VERSION 5.7 ;
  NOWIREEXTENSIONATPIN ON ;
  DIVIDERCHAR "/" ;
  BUSBITCHARS "[]" ;
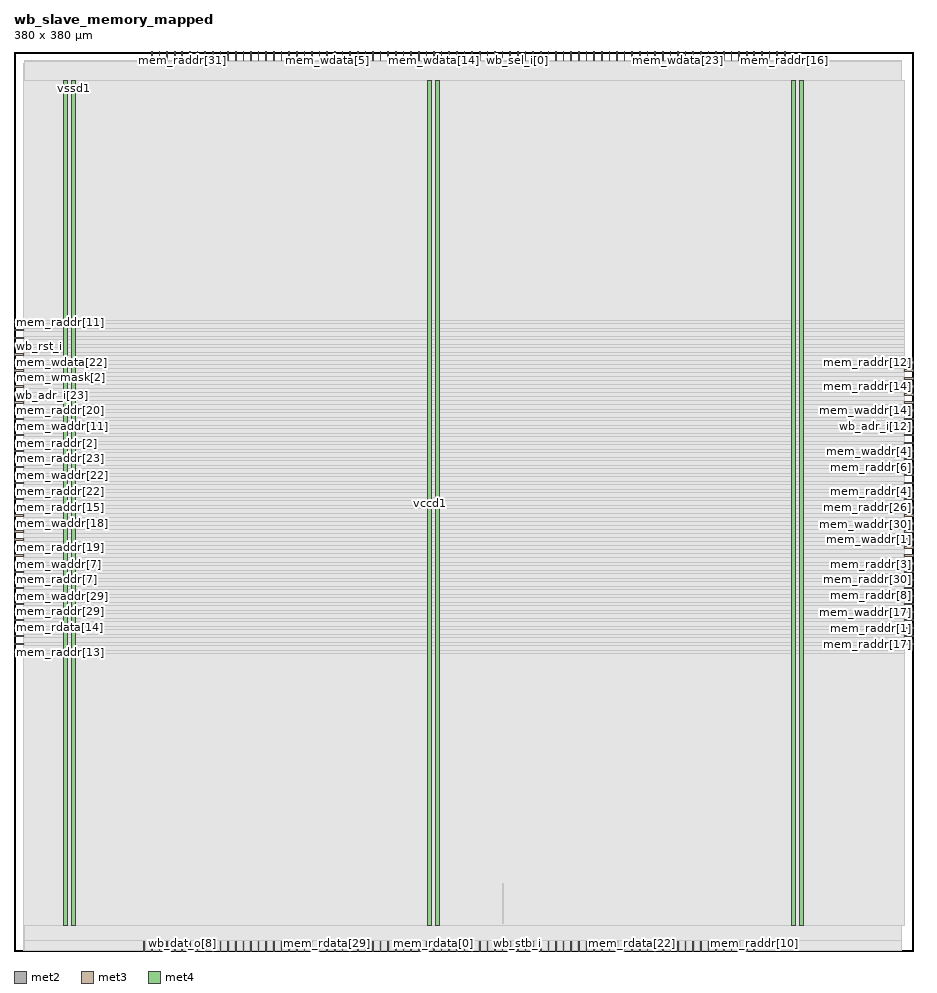
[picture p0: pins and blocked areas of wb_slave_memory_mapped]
MACRO wb_slave_memory_mapped
  CLASS BLOCK ;
  FOREIGN wb_slave_memory_mapped ;
  ORIGIN 0.000 0.000 ;
  SIZE 380.000 BY 380.000 ;
  PIN mem_raddr[0]
    DIRECTION OUTPUT ;
    USE SIGNAL ;
    ANTENNADIFFAREA 0.340600 ;
    PORT
      LAYER met2 ;
        RECT 54.830 0.000 55.110 4.000 ;
    END
  END mem_raddr[0]
  PIN mem_raddr[10]
    DIRECTION OUTPUT ;
    USE SIGNAL ;
    ANTENNADIFFAREA 0.340600 ;
    PORT
      LAYER met2 ;
        RECT 312.430 0.000 312.710 4.000 ;
    END
  END mem_raddr[10]
  PIN mem_raddr[11]
    DIRECTION OUTPUT ;
    USE SIGNAL ;
    ANTENNADIFFAREA 0.340600 ;
    PORT
      LAYER met3 ;
        RECT 0.000 265.240 4.000 265.840 ;
    END
  END mem_raddr[11]
  PIN mem_raddr[12]
    DIRECTION OUTPUT ;
    USE SIGNAL ;
    ANTENNADIFFAREA 0.340600 ;
    PORT
      LAYER met3 ;
        RECT 376.000 248.240 380.000 248.840 ;
    END
  END mem_raddr[12]
  PIN mem_raddr[13]
    DIRECTION OUTPUT ;
    USE SIGNAL ;
    ANTENNADIFFAREA 0.340600 ;
    PORT
      LAYER met3 ;
        RECT 0.000 125.840 4.000 126.440 ;
    END
  END mem_raddr[13]
  PIN mem_raddr[14]
    DIRECTION OUTPUT ;
    USE SIGNAL ;
    ANTENNADIFFAREA 0.340600 ;
    PORT
      LAYER met3 ;
        RECT 376.000 238.040 380.000 238.640 ;
    END
  END mem_raddr[14]
  PIN mem_raddr[15]
    DIRECTION OUTPUT ;
    USE SIGNAL ;
    ANTENNADIFFAREA 0.340600 ;
    PORT
      LAYER met3 ;
        RECT 0.000 187.040 4.000 187.640 ;
    END
  END mem_raddr[15]
  PIN mem_raddr[16]
    DIRECTION OUTPUT ;
    USE SIGNAL ;
    ANTENNADIFFAREA 0.340600 ;
    PORT
      LAYER met2 ;
        RECT 325.310 376.000 325.590 380.000 ;
    END
  END mem_raddr[16]
  PIN mem_raddr[17]
    DIRECTION OUTPUT ;
    USE SIGNAL ;
    ANTENNADIFFAREA 0.340600 ;
    PORT
      LAYER met3 ;
        RECT 376.000 129.240 380.000 129.840 ;
    END
  END mem_raddr[17]
  PIN mem_raddr[18]
    DIRECTION OUTPUT ;
    USE SIGNAL ;
    ANTENNADIFFAREA 0.340600 ;
    PORT
      LAYER met3 ;
        RECT 0.000 132.640 4.000 133.240 ;
    END
  END mem_raddr[18]
  PIN mem_raddr[19]
    DIRECTION OUTPUT ;
    USE SIGNAL ;
    ANTENNADIFFAREA 0.340600 ;
    PORT
      LAYER met3 ;
        RECT 0.000 170.040 4.000 170.640 ;
    END
  END mem_raddr[19]
  PIN mem_raddr[1]
    DIRECTION OUTPUT ;
    USE SIGNAL ;
    ANTENNADIFFAREA 0.340600 ;
    PORT
      LAYER met3 ;
        RECT 376.000 136.040 380.000 136.640 ;
    END
  END mem_raddr[1]
  PIN mem_raddr[20]
    DIRECTION OUTPUT ;
    USE SIGNAL ;
    ANTENNADIFFAREA 0.340600 ;
    PORT
      LAYER met3 ;
        RECT 0.000 227.840 4.000 228.440 ;
    END
  END mem_raddr[20]
  PIN mem_raddr[21]
    DIRECTION OUTPUT ;
    USE SIGNAL ;
    ANTENNADIFFAREA 0.340600 ;
    PORT
      LAYER met2 ;
        RECT 299.550 376.000 299.830 380.000 ;
    END
  END mem_raddr[21]
  PIN mem_raddr[22]
    DIRECTION OUTPUT ;
    USE SIGNAL ;
    ANTENNADIFFAREA 0.340600 ;
    PORT
      LAYER met3 ;
        RECT 0.000 193.840 4.000 194.440 ;
    END
  END mem_raddr[22]
  PIN mem_raddr[23]
    DIRECTION OUTPUT ;
    USE SIGNAL ;
    ANTENNADIFFAREA 0.340600 ;
    PORT
      LAYER met3 ;
        RECT 0.000 207.440 4.000 208.040 ;
    END
  END mem_raddr[23]
  PIN mem_raddr[24]
    DIRECTION OUTPUT ;
    USE SIGNAL ;
    ANTENNADIFFAREA 0.340600 ;
    PORT
      LAYER met3 ;
        RECT 376.000 200.640 380.000 201.240 ;
    END
  END mem_raddr[24]
  PIN mem_raddr[25]
    DIRECTION OUTPUT ;
    USE SIGNAL ;
    ANTENNADIFFAREA 0.340600 ;
    PORT
      LAYER met2 ;
        RECT 58.050 376.000 58.330 380.000 ;
    END
  END mem_raddr[25]
  PIN mem_raddr[26]
    DIRECTION OUTPUT ;
    USE SIGNAL ;
    ANTENNADIFFAREA 0.340600 ;
    PORT
      LAYER met3 ;
        RECT 376.000 187.040 380.000 187.640 ;
    END
  END mem_raddr[26]
  PIN mem_raddr[27]
    DIRECTION OUTPUT ;
    USE SIGNAL ;
    ANTENNADIFFAREA 0.340600 ;
    PORT
      LAYER met2 ;
        RECT 193.290 376.000 193.570 380.000 ;
    END
  END mem_raddr[27]
  PIN mem_raddr[28]
    DIRECTION OUTPUT ;
    USE SIGNAL ;
    ANTENNADIFFAREA 0.340600 ;
    PORT
      LAYER met2 ;
        RECT 309.210 0.000 309.490 4.000 ;
    END
  END mem_raddr[28]
  PIN mem_raddr[29]
    DIRECTION OUTPUT ;
    USE SIGNAL ;
    ANTENNADIFFAREA 0.340600 ;
    PORT
      LAYER met3 ;
        RECT 0.000 142.840 4.000 143.440 ;
    END
  END mem_raddr[29]
  PIN mem_raddr[2]
    DIRECTION OUTPUT ;
    USE SIGNAL ;
    ANTENNADIFFAREA 0.340600 ;
    PORT
      LAYER met3 ;
        RECT 0.000 210.840 4.000 211.440 ;
    END
  END mem_raddr[2]
  PIN mem_raddr[30]
    DIRECTION OUTPUT ;
    USE SIGNAL ;
    ANTENNADIFFAREA 0.340600 ;
    PORT
      LAYER met3 ;
        RECT 376.000 156.440 380.000 157.040 ;
    END
  END mem_raddr[30]
  PIN mem_raddr[31]
    DIRECTION OUTPUT ;
    USE SIGNAL ;
    ANTENNADIFFAREA 0.340600 ;
    PORT
      LAYER met2 ;
        RECT 70.930 376.000 71.210 380.000 ;
    END
  END mem_raddr[31]
  PIN mem_raddr[3]
    DIRECTION OUTPUT ;
    USE SIGNAL ;
    ANTENNADIFFAREA 0.340600 ;
    PORT
      LAYER met3 ;
        RECT 376.000 159.840 380.000 160.440 ;
    END
  END mem_raddr[3]
  PIN mem_raddr[4]
    DIRECTION OUTPUT ;
    USE SIGNAL ;
    ANTENNADIFFAREA 0.340600 ;
    PORT
      LAYER met3 ;
        RECT 376.000 190.440 380.000 191.040 ;
    END
  END mem_raddr[4]
  PIN mem_raddr[5]
    DIRECTION OUTPUT ;
    USE SIGNAL ;
    ANTENNADIFFAREA 0.340600 ;
    PORT
      LAYER met2 ;
        RECT 80.590 0.000 80.870 4.000 ;
    END
  END mem_raddr[5]
  PIN mem_raddr[6]
    DIRECTION OUTPUT ;
    USE SIGNAL ;
    ANTENNADIFFAREA 0.340600 ;
    PORT
      LAYER met3 ;
        RECT 376.000 204.040 380.000 204.640 ;
    END
  END mem_raddr[6]
  PIN mem_raddr[7]
    DIRECTION OUTPUT ;
    USE SIGNAL ;
    ANTENNADIFFAREA 0.340600 ;
    PORT
      LAYER met3 ;
        RECT 0.000 156.440 4.000 157.040 ;
    END
  END mem_raddr[7]
  PIN mem_raddr[8]
    DIRECTION OUTPUT ;
    USE SIGNAL ;
    ANTENNADIFFAREA 0.340600 ;
    PORT
      LAYER met3 ;
        RECT 376.000 153.040 380.000 153.640 ;
    END
  END mem_raddr[8]
  PIN mem_raddr[9]
    DIRECTION OUTPUT ;
    USE SIGNAL ;
    ANTENNADIFFAREA 0.340600 ;
    PORT
      LAYER met3 ;
        RECT 376.000 234.640 380.000 235.240 ;
    END
  END mem_raddr[9]
  PIN mem_rdata[0]
    DIRECTION INPUT ;
    USE SIGNAL ;
    ANTENNAGATEAREA 0.631200 ;
    ANTENNADIFFAREA 0.434700 ;
    PORT
      LAYER met2 ;
        RECT 177.190 0.000 177.470 4.000 ;
    END
  END mem_rdata[0]
  PIN mem_rdata[10]
    DIRECTION INPUT ;
    USE SIGNAL ;
    ANTENNAGATEAREA 0.631200 ;
    ANTENNADIFFAREA 0.434700 ;
    PORT
      LAYER met2 ;
        RECT 93.470 0.000 93.750 4.000 ;
    END
  END mem_rdata[10]
  PIN mem_rdata[11]
    DIRECTION INPUT ;
    USE SIGNAL ;
    ANTENNAGATEAREA 0.631200 ;
    ANTENNADIFFAREA 0.434700 ;
    PORT
      LAYER met2 ;
        RECT 190.070 0.000 190.350 4.000 ;
    END
  END mem_rdata[11]
  PIN mem_rdata[12]
    DIRECTION INPUT ;
    USE SIGNAL ;
    ANTENNAGATEAREA 0.631200 ;
    ANTENNADIFFAREA 0.434700 ;
    PORT
      LAYER met2 ;
        RECT 296.330 0.000 296.610 4.000 ;
    END
  END mem_rdata[12]
  PIN mem_rdata[13]
    DIRECTION INPUT ;
    USE SIGNAL ;
    ANTENNAGATEAREA 0.631200 ;
    ANTENNADIFFAREA 0.434700 ;
    PORT
      LAYER met2 ;
        RECT 96.690 0.000 96.970 4.000 ;
    END
  END mem_rdata[13]
  PIN mem_rdata[14]
    DIRECTION INPUT ;
    USE SIGNAL ;
    ANTENNAGATEAREA 0.631200 ;
    ANTENNADIFFAREA 0.434700 ;
    PORT
      LAYER met3 ;
        RECT 0.000 139.440 4.000 140.040 ;
    END
  END mem_rdata[14]
  PIN mem_rdata[15]
    DIRECTION INPUT ;
    USE SIGNAL ;
    ANTENNAGATEAREA 0.560700 ;
    ANTENNADIFFAREA 0.434700 ;
    PORT
      LAYER met3 ;
        RECT 0.000 129.240 4.000 129.840 ;
    END
  END mem_rdata[15]
  PIN mem_rdata[16]
    DIRECTION INPUT ;
    USE SIGNAL ;
    ANTENNAGATEAREA 0.631200 ;
    ANTENNADIFFAREA 0.434700 ;
    PORT
      LAYER met2 ;
        RECT 148.210 0.000 148.490 4.000 ;
    END
  END mem_rdata[16]
  PIN mem_rdata[17]
    DIRECTION INPUT ;
    USE SIGNAL ;
    ANTENNAGATEAREA 0.631200 ;
    ANTENNADIFFAREA 0.434700 ;
    PORT
      LAYER met2 ;
        RECT 196.510 0.000 196.790 4.000 ;
    END
  END mem_rdata[17]
  PIN mem_rdata[18]
    DIRECTION INPUT ;
    USE SIGNAL ;
    ANTENNAGATEAREA 0.631200 ;
    ANTENNADIFFAREA 0.434700 ;
    PORT
      LAYER met2 ;
        RECT 293.110 0.000 293.390 4.000 ;
    END
  END mem_rdata[18]
  PIN mem_rdata[19]
    DIRECTION INPUT ;
    USE SIGNAL ;
    ANTENNAGATEAREA 0.631200 ;
    ANTENNADIFFAREA 0.434700 ;
    PORT
      LAYER met2 ;
        RECT 231.930 0.000 232.210 4.000 ;
    END
  END mem_rdata[19]
  PIN mem_rdata[1]
    DIRECTION INPUT ;
    USE SIGNAL ;
    ANTENNAGATEAREA 0.631200 ;
    ANTENNADIFFAREA 0.434700 ;
    PORT
      LAYER met2 ;
        RECT 138.550 0.000 138.830 4.000 ;
    END
  END mem_rdata[1]
  PIN mem_rdata[20]
    DIRECTION INPUT ;
    USE SIGNAL ;
    ANTENNAGATEAREA 0.631200 ;
    ANTENNADIFFAREA 0.434700 ;
    PORT
      LAYER met2 ;
        RECT 103.130 0.000 103.410 4.000 ;
    END
  END mem_rdata[20]
  PIN mem_rdata[21]
    DIRECTION INPUT ;
    USE SIGNAL ;
    ANTENNAGATEAREA 0.631200 ;
    ANTENNADIFFAREA 0.434700 ;
    PORT
      LAYER met2 ;
        RECT 228.710 0.000 228.990 4.000 ;
    END
  END mem_rdata[21]
  PIN mem_rdata[22]
    DIRECTION INPUT ;
    USE SIGNAL ;
    ANTENNAGATEAREA 0.631200 ;
    ANTENNADIFFAREA 0.434700 ;
    PORT
      LAYER met2 ;
        RECT 260.910 0.000 261.190 4.000 ;
    END
  END mem_rdata[22]
  PIN mem_rdata[23]
    DIRECTION INPUT ;
    USE SIGNAL ;
    ANTENNAGATEAREA 0.631200 ;
    ANTENNADIFFAREA 0.434700 ;
    PORT
      LAYER met2 ;
        RECT 74.150 0.000 74.430 4.000 ;
    END
  END mem_rdata[23]
  PIN mem_rdata[24]
    DIRECTION INPUT ;
    USE SIGNAL ;
    ANTENNAGATEAREA 0.631200 ;
    ANTENNADIFFAREA 0.434700 ;
    PORT
      LAYER met2 ;
        RECT 254.470 0.000 254.750 4.000 ;
    END
  END mem_rdata[24]
  PIN mem_rdata[25]
    DIRECTION INPUT ;
    USE SIGNAL ;
    ANTENNAGATEAREA 0.631200 ;
    ANTENNADIFFAREA 0.434700 ;
    PORT
      LAYER met2 ;
        RECT 215.830 0.000 216.110 4.000 ;
    END
  END mem_rdata[25]
  PIN mem_rdata[26]
    DIRECTION INPUT ;
    USE SIGNAL ;
    ANTENNAGATEAREA 0.631200 ;
    ANTENNADIFFAREA 0.434700 ;
    PORT
      LAYER met2 ;
        RECT 167.530 0.000 167.810 4.000 ;
    END
  END mem_rdata[26]
  PIN mem_rdata[27]
    DIRECTION INPUT ;
    USE SIGNAL ;
    ANTENNAGATEAREA 0.631200 ;
    ANTENNADIFFAREA 0.434700 ;
    PORT
      LAYER met2 ;
        RECT 251.250 0.000 251.530 4.000 ;
    END
  END mem_rdata[27]
  PIN mem_rdata[28]
    DIRECTION INPUT ;
    USE SIGNAL ;
    ANTENNAGATEAREA 0.631200 ;
    ANTENNADIFFAREA 0.434700 ;
    PORT
      LAYER met2 ;
        RECT 267.350 0.000 267.630 4.000 ;
    END
  END mem_rdata[28]
  PIN mem_rdata[29]
    DIRECTION INPUT ;
    USE SIGNAL ;
    ANTENNAGATEAREA 0.631200 ;
    ANTENNADIFFAREA 0.434700 ;
    PORT
      LAYER met2 ;
        RECT 132.110 0.000 132.390 4.000 ;
    END
  END mem_rdata[29]
  PIN mem_rdata[2]
    DIRECTION INPUT ;
    USE SIGNAL ;
    ANTENNAGATEAREA 0.631200 ;
    ANTENNADIFFAREA 0.434700 ;
    PORT
      LAYER met2 ;
        RECT 106.350 0.000 106.630 4.000 ;
    END
  END mem_rdata[2]
  PIN mem_rdata[30]
    DIRECTION INPUT ;
    USE SIGNAL ;
    ANTENNAGATEAREA 0.631200 ;
    ANTENNADIFFAREA 0.434700 ;
    PORT
      LAYER met2 ;
        RECT 286.670 0.000 286.950 4.000 ;
    END
  END mem_rdata[30]
  PIN mem_rdata[31]
    DIRECTION INPUT ;
    USE SIGNAL ;
    ANTENNAGATEAREA 0.631200 ;
    ANTENNADIFFAREA 0.434700 ;
    PORT
      LAYER met2 ;
        RECT 83.810 0.000 84.090 4.000 ;
    END
  END mem_rdata[31]
  PIN mem_rdata[3]
    DIRECTION INPUT ;
    USE SIGNAL ;
    ANTENNAGATEAREA 0.631200 ;
    ANTENNADIFFAREA 0.434700 ;
    PORT
      LAYER met2 ;
        RECT 289.890 0.000 290.170 4.000 ;
    END
  END mem_rdata[3]
  PIN mem_rdata[4]
    DIRECTION INPUT ;
    USE SIGNAL ;
    ANTENNAGATEAREA 0.631200 ;
    ANTENNADIFFAREA 0.434700 ;
    PORT
      LAYER met2 ;
        RECT 154.650 0.000 154.930 4.000 ;
    END
  END mem_rdata[4]
  PIN mem_rdata[5]
    DIRECTION INPUT ;
    USE SIGNAL ;
    ANTENNAGATEAREA 0.631200 ;
    ANTENNADIFFAREA 0.434700 ;
    PORT
      LAYER met2 ;
        RECT 248.030 0.000 248.310 4.000 ;
    END
  END mem_rdata[5]
  PIN mem_rdata[6]
    DIRECTION INPUT ;
    USE SIGNAL ;
    ANTENNAGATEAREA 0.631200 ;
    ANTENNADIFFAREA 0.434700 ;
    PORT
      LAYER met2 ;
        RECT 225.490 0.000 225.770 4.000 ;
    END
  END mem_rdata[6]
  PIN mem_rdata[7]
    DIRECTION INPUT ;
    USE SIGNAL ;
    ANTENNAGATEAREA 0.631200 ;
    ANTENNADIFFAREA 0.434700 ;
    PORT
      LAYER met2 ;
        RECT 125.670 0.000 125.950 4.000 ;
    END
  END mem_rdata[7]
  PIN mem_rdata[8]
    DIRECTION INPUT ;
    USE SIGNAL ;
    ANTENNAGATEAREA 0.631200 ;
    ANTENNADIFFAREA 0.434700 ;
    PORT
      LAYER met2 ;
        RECT 170.750 0.000 171.030 4.000 ;
    END
  END mem_rdata[8]
  PIN mem_rdata[9]
    DIRECTION INPUT ;
    USE SIGNAL ;
    ANTENNAGATEAREA 0.631200 ;
    ANTENNADIFFAREA 0.434700 ;
    PORT
      LAYER met2 ;
        RECT 122.450 0.000 122.730 4.000 ;
    END
  END mem_rdata[9]
  PIN mem_rdy
    DIRECTION INPUT ;
    USE SIGNAL ;
    ANTENNAGATEAREA 0.593700 ;
    ANTENNADIFFAREA 0.434700 ;
    PORT
      LAYER met2 ;
        RECT 64.490 0.000 64.770 4.000 ;
    END
  END mem_rdy
  PIN mem_re
    DIRECTION OUTPUT ;
    USE SIGNAL ;
    ANTENNADIFFAREA 0.340600 ;
    PORT
      LAYER met2 ;
        RECT 270.570 0.000 270.850 4.000 ;
    END
  END mem_re
  PIN mem_waddr[0]
    DIRECTION OUTPUT ;
    USE SIGNAL ;
    ANTENNADIFFAREA 0.340600 ;
    PORT
      LAYER met2 ;
        RECT 119.230 0.000 119.510 4.000 ;
    END
  END mem_waddr[0]
  PIN mem_waddr[10]
    DIRECTION OUTPUT ;
    USE SIGNAL ;
    ANTENNADIFFAREA 0.340600 ;
    PORT
      LAYER met2 ;
        RECT 58.050 0.000 58.330 4.000 ;
    END
  END mem_waddr[10]
  PIN mem_waddr[11]
    DIRECTION OUTPUT ;
    USE SIGNAL ;
    ANTENNADIFFAREA 0.340600 ;
    PORT
      LAYER met3 ;
        RECT 0.000 221.040 4.000 221.640 ;
    END
  END mem_waddr[11]
  PIN mem_waddr[12]
    DIRECTION OUTPUT ;
    USE SIGNAL ;
    ANTENNADIFFAREA 0.340600 ;
    PORT
      LAYER met3 ;
        RECT 376.000 217.640 380.000 218.240 ;
    END
  END mem_waddr[12]
  PIN mem_waddr[13]
    DIRECTION OUTPUT ;
    USE SIGNAL ;
    ANTENNADIFFAREA 0.340600 ;
    PORT
      LAYER met3 ;
        RECT 0.000 251.640 4.000 252.240 ;
    END
  END mem_waddr[13]
  PIN mem_waddr[14]
    DIRECTION OUTPUT ;
    USE SIGNAL ;
    ANTENNADIFFAREA 0.340600 ;
    PORT
      LAYER met3 ;
        RECT 376.000 227.840 380.000 228.440 ;
    END
  END mem_waddr[14]
  PIN mem_waddr[15]
    DIRECTION OUTPUT ;
    USE SIGNAL ;
    ANTENNADIFFAREA 0.340600 ;
    PORT
      LAYER met3 ;
        RECT 0.000 190.440 4.000 191.040 ;
    END
  END mem_waddr[15]
  PIN mem_waddr[16]
    DIRECTION OUTPUT ;
    USE SIGNAL ;
    ANTENNADIFFAREA 0.340600 ;
    PORT
      LAYER met2 ;
        RECT 215.830 376.000 216.110 380.000 ;
    END
  END mem_waddr[16]
  PIN mem_waddr[17]
    DIRECTION OUTPUT ;
    USE SIGNAL ;
    ANTENNADIFFAREA 0.340600 ;
    PORT
      LAYER met3 ;
        RECT 376.000 139.440 380.000 140.040 ;
    END
  END mem_waddr[17]
  PIN mem_waddr[18]
    DIRECTION OUTPUT ;
    USE SIGNAL ;
    ANTENNADIFFAREA 0.340600 ;
    PORT
      LAYER met3 ;
        RECT 0.000 180.240 4.000 180.840 ;
    END
  END mem_waddr[18]
  PIN mem_waddr[19]
    DIRECTION OUTPUT ;
    USE SIGNAL ;
    ANTENNADIFFAREA 0.340600 ;
    PORT
      LAYER met3 ;
        RECT 0.000 173.440 4.000 174.040 ;
    END
  END mem_waddr[19]
  PIN mem_waddr[1]
    DIRECTION OUTPUT ;
    USE SIGNAL ;
    ANTENNADIFFAREA 0.340600 ;
    PORT
      LAYER met3 ;
        RECT 376.000 173.440 380.000 174.040 ;
    END
  END mem_waddr[1]
  PIN mem_waddr[20]
    DIRECTION OUTPUT ;
    USE SIGNAL ;
    ANTENNADIFFAREA 0.340600 ;
    PORT
      LAYER met2 ;
        RECT 83.810 376.000 84.090 380.000 ;
    END
  END mem_waddr[20]
  PIN mem_waddr[21]
    DIRECTION OUTPUT ;
    USE SIGNAL ;
    ANTENNADIFFAREA 0.340600 ;
    PORT
      LAYER met2 ;
        RECT 302.770 376.000 303.050 380.000 ;
    END
  END mem_waddr[21]
  PIN mem_waddr[22]
    DIRECTION OUTPUT ;
    USE SIGNAL ;
    ANTENNADIFFAREA 0.340600 ;
    PORT
      LAYER met3 ;
        RECT 0.000 197.240 4.000 197.840 ;
    END
  END mem_waddr[22]
  PIN mem_waddr[23]
    DIRECTION OUTPUT ;
    USE SIGNAL ;
    ANTENNADIFFAREA 0.340600 ;
    PORT
      LAYER met3 ;
        RECT 0.000 234.640 4.000 235.240 ;
    END
  END mem_waddr[23]
  PIN mem_waddr[24]
    DIRECTION OUTPUT ;
    USE SIGNAL ;
    ANTENNADIFFAREA 0.340600 ;
    PORT
      LAYER met3 ;
        RECT 376.000 197.240 380.000 197.840 ;
    END
  END mem_waddr[24]
  PIN mem_waddr[25]
    DIRECTION OUTPUT ;
    USE SIGNAL ;
    ANTENNADIFFAREA 0.340600 ;
    PORT
      LAYER met2 ;
        RECT 164.310 376.000 164.590 380.000 ;
    END
  END mem_waddr[25]
  PIN mem_waddr[26]
    DIRECTION OUTPUT ;
    USE SIGNAL ;
    ANTENNADIFFAREA 0.340600 ;
    PORT
      LAYER met3 ;
        RECT 376.000 183.640 380.000 184.240 ;
    END
  END mem_waddr[26]
  PIN mem_waddr[27]
    DIRECTION OUTPUT ;
    USE SIGNAL ;
    ANTENNADIFFAREA 0.340600 ;
    PORT
      LAYER met2 ;
        RECT 196.510 376.000 196.790 380.000 ;
    END
  END mem_waddr[27]
  PIN mem_waddr[28]
    DIRECTION OUTPUT ;
    USE SIGNAL ;
    ANTENNADIFFAREA 0.340600 ;
    PORT
      LAYER met2 ;
        RECT 302.770 0.000 303.050 4.000 ;
    END
  END mem_waddr[28]
  PIN mem_waddr[29]
    DIRECTION OUTPUT ;
    USE SIGNAL ;
    ANTENNADIFFAREA 0.340600 ;
    PORT
      LAYER met3 ;
        RECT 0.000 146.240 4.000 146.840 ;
    END
  END mem_waddr[29]
  PIN mem_waddr[2]
    DIRECTION OUTPUT ;
    USE SIGNAL ;
    ANTENNADIFFAREA 0.340600 ;
    PORT
      LAYER met3 ;
        RECT 0.000 217.640 4.000 218.240 ;
    END
  END mem_waddr[2]
  PIN mem_waddr[30]
    DIRECTION OUTPUT ;
    USE SIGNAL ;
    ANTENNADIFFAREA 0.340600 ;
    PORT
      LAYER met3 ;
        RECT 376.000 176.840 380.000 177.440 ;
    END
  END mem_waddr[30]
  PIN mem_waddr[31]
    DIRECTION OUTPUT ;
    USE SIGNAL ;
    ANTENNADIFFAREA 0.340600 ;
    PORT
      LAYER met2 ;
        RECT 148.210 376.000 148.490 380.000 ;
    END
  END mem_waddr[31]
  PIN mem_waddr[3]
    DIRECTION OUTPUT ;
    USE SIGNAL ;
    ANTENNADIFFAREA 0.340600 ;
    PORT
      LAYER met3 ;
        RECT 376.000 163.240 380.000 163.840 ;
    END
  END mem_waddr[3]
  PIN mem_waddr[4]
    DIRECTION OUTPUT ;
    USE SIGNAL ;
    ANTENNADIFFAREA 0.340600 ;
    PORT
      LAYER met3 ;
        RECT 376.000 207.440 380.000 208.040 ;
    END
  END mem_waddr[4]
  PIN mem_waddr[5]
    DIRECTION OUTPUT ;
    USE SIGNAL ;
    ANTENNADIFFAREA 0.340600 ;
    PORT
      LAYER met2 ;
        RECT 161.090 0.000 161.370 4.000 ;
    END
  END mem_waddr[5]
  PIN mem_waddr[6]
    DIRECTION OUTPUT ;
    USE SIGNAL ;
    ANTENNADIFFAREA 0.340600 ;
    PORT
      LAYER met3 ;
        RECT 376.000 210.840 380.000 211.440 ;
    END
  END mem_waddr[6]
  PIN mem_waddr[7]
    DIRECTION OUTPUT ;
    USE SIGNAL ;
    ANTENNADIFFAREA 0.340600 ;
    PORT
      LAYER met3 ;
        RECT 0.000 159.840 4.000 160.440 ;
    END
  END mem_waddr[7]
  PIN mem_waddr[8]
    DIRECTION OUTPUT ;
    USE SIGNAL ;
    ANTENNADIFFAREA 0.340600 ;
    PORT
      LAYER met3 ;
        RECT 376.000 146.240 380.000 146.840 ;
    END
  END mem_waddr[8]
  PIN mem_waddr[9]
    DIRECTION OUTPUT ;
    USE SIGNAL ;
    ANTENNADIFFAREA 0.340600 ;
    PORT
      LAYER met3 ;
        RECT 376.000 241.440 380.000 242.040 ;
    END
  END mem_waddr[9]
  PIN mem_wdata[0]
    DIRECTION OUTPUT ;
    USE SIGNAL ;
    ANTENNADIFFAREA 0.340600 ;
    PORT
      LAYER met2 ;
        RECT 90.250 376.000 90.530 380.000 ;
    END
  END mem_wdata[0]
  PIN mem_wdata[10]
    DIRECTION OUTPUT ;
    USE SIGNAL ;
    ANTENNADIFFAREA 0.340600 ;
    PORT
      LAYER met2 ;
        RECT 74.150 376.000 74.430 380.000 ;
    END
  END mem_wdata[10]
  PIN mem_wdata[11]
    DIRECTION OUTPUT ;
    USE SIGNAL ;
    ANTENNADIFFAREA 0.340600 ;
    PORT
      LAYER met2 ;
        RECT 151.430 376.000 151.710 380.000 ;
    END
  END mem_wdata[11]
  PIN mem_wdata[12]
    DIRECTION OUTPUT ;
    USE SIGNAL ;
    ANTENNADIFFAREA 0.340600 ;
    PORT
      LAYER met2 ;
        RECT 87.030 376.000 87.310 380.000 ;
    END
  END mem_wdata[12]
  PIN mem_wdata[13]
    DIRECTION OUTPUT ;
    USE SIGNAL ;
    ANTENNADIFFAREA 0.340600 ;
    PORT
      LAYER met2 ;
        RECT 96.690 376.000 96.970 380.000 ;
    END
  END mem_wdata[13]
  PIN mem_wdata[14]
    DIRECTION OUTPUT ;
    USE SIGNAL ;
    ANTENNADIFFAREA 0.340600 ;
    PORT
      LAYER met2 ;
        RECT 177.190 376.000 177.470 380.000 ;
    END
  END mem_wdata[14]
  PIN mem_wdata[15]
    DIRECTION OUTPUT ;
    USE SIGNAL ;
    ANTENNADIFFAREA 0.340600 ;
    PORT
      LAYER met2 ;
        RECT 309.210 376.000 309.490 380.000 ;
    END
  END mem_wdata[15]
  PIN mem_wdata[16]
    DIRECTION OUTPUT ;
    USE SIGNAL ;
    ANTENNADIFFAREA 0.340600 ;
    PORT
      LAYER met2 ;
        RECT 289.890 376.000 290.170 380.000 ;
    END
  END mem_wdata[16]
  PIN mem_wdata[17]
    DIRECTION OUTPUT ;
    USE SIGNAL ;
    ANTENNADIFFAREA 0.340600 ;
    PORT
      LAYER met2 ;
        RECT 283.450 376.000 283.730 380.000 ;
    END
  END mem_wdata[17]
  PIN mem_wdata[18]
    DIRECTION OUTPUT ;
    USE SIGNAL ;
    ANTENNADIFFAREA 0.340600 ;
    PORT
      LAYER met2 ;
        RECT 186.850 376.000 187.130 380.000 ;
    END
  END mem_wdata[18]
  PIN mem_wdata[19]
    DIRECTION OUTPUT ;
    USE SIGNAL ;
    ANTENNADIFFAREA 0.340600 ;
    PORT
      LAYER met2 ;
        RECT 254.470 376.000 254.750 380.000 ;
    END
  END mem_wdata[19]
  PIN mem_wdata[1]
    DIRECTION OUTPUT ;
    USE SIGNAL ;
    ANTENNADIFFAREA 0.340600 ;
    PORT
      LAYER met2 ;
        RECT 93.470 376.000 93.750 380.000 ;
    END
  END mem_wdata[1]
  PIN mem_wdata[20]
    DIRECTION OUTPUT ;
    USE SIGNAL ;
    ANTENNADIFFAREA 0.340600 ;
    PORT
      LAYER met2 ;
        RECT 128.890 376.000 129.170 380.000 ;
    END
  END mem_wdata[20]
  PIN mem_wdata[21]
    DIRECTION OUTPUT ;
    USE SIGNAL ;
    ANTENNADIFFAREA 0.340600 ;
    PORT
      LAYER met2 ;
        RECT 80.590 376.000 80.870 380.000 ;
    END
  END mem_wdata[21]
  PIN mem_wdata[22]
    DIRECTION OUTPUT ;
    USE SIGNAL ;
    ANTENNADIFFAREA 0.340600 ;
    PORT
      LAYER met3 ;
        RECT 0.000 248.240 4.000 248.840 ;
    END
  END mem_wdata[22]
  PIN mem_wdata[23]
    DIRECTION OUTPUT ;
    USE SIGNAL ;
    ANTENNADIFFAREA 0.340600 ;
    PORT
      LAYER met2 ;
        RECT 280.230 376.000 280.510 380.000 ;
    END
  END mem_wdata[23]
  PIN mem_wdata[24]
    DIRECTION OUTPUT ;
    USE SIGNAL ;
    ANTENNADIFFAREA 0.340600 ;
    PORT
      LAYER met2 ;
        RECT 135.330 376.000 135.610 380.000 ;
    END
  END mem_wdata[24]
  PIN mem_wdata[25]
    DIRECTION OUTPUT ;
    USE SIGNAL ;
    ANTENNADIFFAREA 0.340600 ;
    PORT
      LAYER met2 ;
        RECT 116.010 376.000 116.290 380.000 ;
    END
  END mem_wdata[25]
  PIN mem_wdata[26]
    DIRECTION OUTPUT ;
    USE SIGNAL ;
    ANTENNADIFFAREA 0.340600 ;
    PORT
      LAYER met2 ;
        RECT 248.030 376.000 248.310 380.000 ;
    END
  END mem_wdata[26]
  PIN mem_wdata[27]
    DIRECTION OUTPUT ;
    USE SIGNAL ;
    ANTENNADIFFAREA 0.340600 ;
    PORT
      LAYER met2 ;
        RECT 293.110 376.000 293.390 380.000 ;
    END
  END mem_wdata[27]
  PIN mem_wdata[28]
    DIRECTION OUTPUT ;
    USE SIGNAL ;
    ANTENNADIFFAREA 0.340600 ;
    PORT
      LAYER met2 ;
        RECT 141.770 376.000 142.050 380.000 ;
    END
  END mem_wdata[28]
  PIN mem_wdata[29]
    DIRECTION OUTPUT ;
    USE SIGNAL ;
    ANTENNADIFFAREA 0.340600 ;
    PORT
      LAYER met2 ;
        RECT 170.750 376.000 171.030 380.000 ;
    END
  END mem_wdata[29]
  PIN mem_wdata[2]
    DIRECTION OUTPUT ;
    USE SIGNAL ;
    ANTENNADIFFAREA 0.340600 ;
    PORT
      LAYER met2 ;
        RECT 251.250 376.000 251.530 380.000 ;
    END
  END mem_wdata[2]
  PIN mem_wdata[30]
    DIRECTION OUTPUT ;
    USE SIGNAL ;
    ANTENNADIFFAREA 0.340600 ;
    PORT
      LAYER met2 ;
        RECT 106.350 376.000 106.630 380.000 ;
    END
  END mem_wdata[30]
  PIN mem_wdata[31]
    DIRECTION OUTPUT ;
    USE SIGNAL ;
    ANTENNADIFFAREA 0.340600 ;
    PORT
      LAYER met2 ;
        RECT 238.370 376.000 238.650 380.000 ;
    END
  END mem_wdata[31]
  PIN mem_wdata[3]
    DIRECTION OUTPUT ;
    USE SIGNAL ;
    ANTENNADIFFAREA 0.340600 ;
    PORT
      LAYER met2 ;
        RECT 235.150 376.000 235.430 380.000 ;
    END
  END mem_wdata[3]
  PIN mem_wdata[4]
    DIRECTION OUTPUT ;
    USE SIGNAL ;
    ANTENNADIFFAREA 0.340600 ;
    PORT
      LAYER met2 ;
        RECT 228.710 376.000 228.990 380.000 ;
    END
  END mem_wdata[4]
  PIN mem_wdata[5]
    DIRECTION OUTPUT ;
    USE SIGNAL ;
    ANTENNADIFFAREA 0.340600 ;
    PORT
      LAYER met2 ;
        RECT 132.110 376.000 132.390 380.000 ;
    END
  END mem_wdata[5]
  PIN mem_wdata[6]
    DIRECTION OUTPUT ;
    USE SIGNAL ;
    ANTENNADIFFAREA 0.340600 ;
    PORT
      LAYER met2 ;
        RECT 312.430 376.000 312.710 380.000 ;
    END
  END mem_wdata[6]
  PIN mem_wdata[7]
    DIRECTION OUTPUT ;
    USE SIGNAL ;
    ANTENNADIFFAREA 0.340600 ;
    PORT
      LAYER met2 ;
        RECT 99.910 376.000 100.190 380.000 ;
    END
  END mem_wdata[7]
  PIN mem_wdata[8]
    DIRECTION OUTPUT ;
    USE SIGNAL ;
    ANTENNADIFFAREA 0.340600 ;
    PORT
      LAYER met2 ;
        RECT 241.590 376.000 241.870 380.000 ;
    END
  END mem_wdata[8]
  PIN mem_wdata[9]
    DIRECTION OUTPUT ;
    USE SIGNAL ;
    ANTENNADIFFAREA 0.340600 ;
    PORT
      LAYER met2 ;
        RECT 315.650 376.000 315.930 380.000 ;
    END
  END mem_wdata[9]
  PIN mem_we
    DIRECTION OUTPUT ;
    USE SIGNAL ;
    ANTENNADIFFAREA 0.340600 ;
    PORT
      LAYER met2 ;
        RECT 186.850 0.000 187.130 4.000 ;
    END
  END mem_we
  PIN mem_wmask[0]
    DIRECTION OUTPUT ;
    USE SIGNAL ;
    ANTENNADIFFAREA 0.340600 ;
    PORT
      LAYER met2 ;
        RECT 219.050 376.000 219.330 380.000 ;
    END
  END mem_wmask[0]
  PIN mem_wmask[1]
    DIRECTION OUTPUT ;
    USE SIGNAL ;
    ANTENNADIFFAREA 0.340600 ;
    PORT
      LAYER met2 ;
        RECT 296.330 376.000 296.610 380.000 ;
    END
  END mem_wmask[1]
  PIN mem_wmask[2]
    DIRECTION OUTPUT ;
    USE SIGNAL ;
    ANTENNADIFFAREA 0.340600 ;
    PORT
      LAYER met3 ;
        RECT 0.000 244.840 4.000 245.440 ;
    END
  END mem_wmask[2]
  PIN mem_wmask[3]
    DIRECTION OUTPUT ;
    USE SIGNAL ;
    ANTENNADIFFAREA 0.340600 ;
    PORT
      LAYER met2 ;
        RECT 257.690 376.000 257.970 380.000 ;
    END
  END mem_wmask[3]
  PIN mem_wr_data_ack
    DIRECTION INPUT ;
    USE SIGNAL ;
    ANTENNAGATEAREA 0.631200 ;
    ANTENNADIFFAREA 0.434700 ;
    PORT
      LAYER met2 ;
        RECT 173.970 0.000 174.250 4.000 ;
    END
  END mem_wr_data_ack
  PIN up_soft_reset
    DIRECTION INPUT ;
    USE SIGNAL ;
    ANTENNAGATEAREA 0.647700 ;
    ANTENNADIFFAREA 0.434700 ;
    PORT
      LAYER met3 ;
        RECT 0.000 261.840 4.000 262.440 ;
    END
  END up_soft_reset
  PIN vccd1
    DIRECTION INOUT ;
    USE POWER ;
    PORT
      LAYER met4 ;
        RECT 21.040 10.640 22.640 367.440 ;
    END
    PORT
      LAYER met4 ;
        RECT 174.640 10.640 176.240 367.440 ;
    END
    PORT
      LAYER met4 ;
        RECT 328.240 10.640 329.840 367.440 ;
    END
  END vccd1
  PIN vssd1
    DIRECTION INOUT ;
    USE GROUND ;
    PORT
      LAYER met4 ;
        RECT 24.340 10.640 25.940 367.440 ;
    END
    PORT
      LAYER met4 ;
        RECT 177.940 10.640 179.540 367.440 ;
    END
    PORT
      LAYER met4 ;
        RECT 331.540 10.640 333.140 367.440 ;
    END
  END vssd1
  PIN wb_ack_o
    DIRECTION OUTPUT ;
    USE SIGNAL ;
    ANTENNADIFFAREA 1.782000 ;
    PORT
      LAYER met2 ;
        RECT 202.950 0.000 203.230 4.000 ;
    END
  END wb_ack_o
  PIN wb_adr_i[0]
    DIRECTION INPUT ;
    USE SIGNAL ;
    ANTENNAGATEAREA 0.560700 ;
    ANTENNADIFFAREA 0.434700 ;
    PORT
      LAYER met3 ;
        RECT 0.000 153.040 4.000 153.640 ;
    END
  END wb_adr_i[0]
  PIN wb_adr_i[10]
    DIRECTION INPUT ;
    USE SIGNAL ;
    ANTENNAGATEAREA 0.560700 ;
    ANTENNADIFFAREA 0.434700 ;
    PORT
      LAYER met2 ;
        RECT 180.410 0.000 180.690 4.000 ;
    END
  END wb_adr_i[10]
  PIN wb_adr_i[11]
    DIRECTION INPUT ;
    USE SIGNAL ;
    ANTENNAGATEAREA 0.560700 ;
    ANTENNADIFFAREA 0.434700 ;
    PORT
      LAYER met3 ;
        RECT 0.000 224.440 4.000 225.040 ;
    END
  END wb_adr_i[11]
  PIN wb_adr_i[12]
    DIRECTION INPUT ;
    USE SIGNAL ;
    ANTENNAGATEAREA 0.560700 ;
    ANTENNADIFFAREA 0.434700 ;
    PORT
      LAYER met3 ;
        RECT 376.000 221.040 380.000 221.640 ;
    END
  END wb_adr_i[12]
  PIN wb_adr_i[13]
    DIRECTION INPUT ;
    USE SIGNAL ;
    ANTENNAGATEAREA 0.560700 ;
    ANTENNADIFFAREA 0.434700 ;
    PORT
      LAYER met3 ;
        RECT 0.000 204.040 4.000 204.640 ;
    END
  END wb_adr_i[13]
  PIN wb_adr_i[14]
    DIRECTION INPUT ;
    USE SIGNAL ;
    ANTENNAGATEAREA 0.560700 ;
    ANTENNADIFFAREA 0.434700 ;
    PORT
      LAYER met3 ;
        RECT 376.000 214.240 380.000 214.840 ;
    END
  END wb_adr_i[14]
  PIN wb_adr_i[15]
    DIRECTION INPUT ;
    USE SIGNAL ;
    ANTENNAGATEAREA 0.560700 ;
    ANTENNADIFFAREA 0.434700 ;
    PORT
      LAYER met3 ;
        RECT 0.000 183.640 4.000 184.240 ;
    END
  END wb_adr_i[15]
  PIN wb_adr_i[16]
    DIRECTION INPUT ;
    USE SIGNAL ;
    ANTENNAGATEAREA 0.560700 ;
    ANTENNADIFFAREA 0.434700 ;
    PORT
      LAYER met2 ;
        RECT 209.390 376.000 209.670 380.000 ;
    END
  END wb_adr_i[16]
  PIN wb_adr_i[17]
    DIRECTION INPUT ;
    USE SIGNAL ;
    ANTENNAGATEAREA 0.560700 ;
    ANTENNADIFFAREA 0.434700 ;
    PORT
      LAYER met3 ;
        RECT 376.000 142.840 380.000 143.440 ;
    END
  END wb_adr_i[17]
  PIN wb_adr_i[18]
    DIRECTION INPUT ;
    USE SIGNAL ;
    ANTENNAGATEAREA 0.560700 ;
    ANTENNADIFFAREA 0.434700 ;
    PORT
      LAYER met3 ;
        RECT 0.000 176.840 4.000 177.440 ;
    END
  END wb_adr_i[18]
  PIN wb_adr_i[19]
    DIRECTION INPUT ;
    USE SIGNAL ;
    ANTENNAGATEAREA 0.560700 ;
    ANTENNADIFFAREA 0.434700 ;
    PORT
      LAYER met3 ;
        RECT 0.000 166.640 4.000 167.240 ;
    END
  END wb_adr_i[19]
  PIN wb_adr_i[1]
    DIRECTION INPUT ;
    USE SIGNAL ;
    ANTENNAGATEAREA 0.560700 ;
    ANTENNADIFFAREA 0.434700 ;
    PORT
      LAYER met3 ;
        RECT 376.000 170.040 380.000 170.640 ;
    END
  END wb_adr_i[1]
  PIN wb_adr_i[20]
    DIRECTION INPUT ;
    USE SIGNAL ;
    ANTENNAGATEAREA 0.560700 ;
    ANTENNADIFFAREA 0.434700 ;
    PORT
      LAYER met2 ;
        RECT 77.370 376.000 77.650 380.000 ;
    END
  END wb_adr_i[20]
  PIN wb_adr_i[21]
    DIRECTION INPUT ;
    USE SIGNAL ;
    ANTENNAGATEAREA 0.560700 ;
    ANTENNADIFFAREA 0.434700 ;
    PORT
      LAYER met2 ;
        RECT 202.950 376.000 203.230 380.000 ;
    END
  END wb_adr_i[21]
  PIN wb_adr_i[22]
    DIRECTION INPUT ;
    USE SIGNAL ;
    ANTENNAGATEAREA 0.560700 ;
    ANTENNADIFFAREA 0.434700 ;
    PORT
      LAYER met3 ;
        RECT 0.000 200.640 4.000 201.240 ;
    END
  END wb_adr_i[22]
  PIN wb_adr_i[23]
    DIRECTION INPUT ;
    USE SIGNAL ;
    ANTENNAGATEAREA 0.560700 ;
    ANTENNADIFFAREA 0.434700 ;
    PORT
      LAYER met3 ;
        RECT 0.000 231.240 4.000 231.840 ;
    END
  END wb_adr_i[23]
  PIN wb_adr_i[24]
    DIRECTION INPUT ;
    USE SIGNAL ;
    ANTENNAGATEAREA 0.560700 ;
    ANTENNADIFFAREA 0.434700 ;
    PORT
      LAYER met3 ;
        RECT 376.000 193.840 380.000 194.440 ;
    END
  END wb_adr_i[24]
  PIN wb_adr_i[25]
    DIRECTION INPUT ;
    USE SIGNAL ;
    ANTENNAGATEAREA 0.560700 ;
    ANTENNADIFFAREA 0.434700 ;
    PORT
      LAYER met2 ;
        RECT 154.650 376.000 154.930 380.000 ;
    END
  END wb_adr_i[25]
  PIN wb_adr_i[26]
    DIRECTION INPUT ;
    USE SIGNAL ;
    ANTENNAGATEAREA 0.560700 ;
    ANTENNADIFFAREA 0.434700 ;
    PORT
      LAYER met3 ;
        RECT 376.000 180.240 380.000 180.840 ;
    END
  END wb_adr_i[26]
  PIN wb_adr_i[27]
    DIRECTION INPUT ;
    USE SIGNAL ;
    ANTENNAGATEAREA 0.560700 ;
    ANTENNADIFFAREA 0.434700 ;
    PORT
      LAYER met2 ;
        RECT 190.070 376.000 190.350 380.000 ;
    END
  END wb_adr_i[27]
  PIN wb_adr_i[28]
    DIRECTION INPUT ;
    USE SIGNAL ;
    ANTENNAGATEAREA 0.560700 ;
    ANTENNADIFFAREA 0.434700 ;
    PORT
      LAYER met2 ;
        RECT 209.390 0.000 209.670 4.000 ;
    END
  END wb_adr_i[28]
  PIN wb_adr_i[29]
    DIRECTION INPUT ;
    USE SIGNAL ;
    ANTENNAGATEAREA 0.560700 ;
    ANTENNADIFFAREA 0.434700 ;
    PORT
      LAYER met3 ;
        RECT 0.000 149.640 4.000 150.240 ;
    END
  END wb_adr_i[29]
  PIN wb_adr_i[2]
    DIRECTION INPUT ;
    USE SIGNAL ;
    ANTENNAGATEAREA 0.560700 ;
    ANTENNADIFFAREA 0.434700 ;
    PORT
      LAYER met3 ;
        RECT 0.000 214.240 4.000 214.840 ;
    END
  END wb_adr_i[2]
  PIN wb_adr_i[30]
    DIRECTION INPUT ;
    USE SIGNAL ;
    ANTENNAGATEAREA 0.560700 ;
    ANTENNADIFFAREA 0.434700 ;
    PORT
      LAYER met3 ;
        RECT 376.000 132.640 380.000 133.240 ;
    END
  END wb_adr_i[30]
  PIN wb_adr_i[31]
    DIRECTION INPUT ;
    USE SIGNAL ;
    ANTENNAGATEAREA 0.560700 ;
    ANTENNADIFFAREA 0.434700 ;
    PORT
      LAYER met2 ;
        RECT 167.530 376.000 167.810 380.000 ;
    END
  END wb_adr_i[31]
  PIN wb_adr_i[3]
    DIRECTION INPUT ;
    USE SIGNAL ;
    ANTENNAGATEAREA 0.560700 ;
    ANTENNADIFFAREA 0.434700 ;
    PORT
      LAYER met3 ;
        RECT 376.000 166.640 380.000 167.240 ;
    END
  END wb_adr_i[3]
  PIN wb_adr_i[4]
    DIRECTION INPUT ;
    USE SIGNAL ;
    ANTENNAGATEAREA 0.560700 ;
    ANTENNADIFFAREA 0.434700 ;
    PORT
      LAYER met3 ;
        RECT 376.000 244.840 380.000 245.440 ;
    END
  END wb_adr_i[4]
  PIN wb_adr_i[5]
    DIRECTION INPUT ;
    USE SIGNAL ;
    ANTENNAGATEAREA 0.560700 ;
    ANTENNADIFFAREA 0.434700 ;
    PORT
      LAYER met2 ;
        RECT 164.310 0.000 164.590 4.000 ;
    END
  END wb_adr_i[5]
  PIN wb_adr_i[6]
    DIRECTION INPUT ;
    USE SIGNAL ;
    ANTENNAGATEAREA 0.560700 ;
    ANTENNADIFFAREA 0.434700 ;
    PORT
      LAYER met3 ;
        RECT 376.000 224.440 380.000 225.040 ;
    END
  END wb_adr_i[6]
  PIN wb_adr_i[7]
    DIRECTION INPUT ;
    USE SIGNAL ;
    ANTENNAGATEAREA 0.560700 ;
    ANTENNADIFFAREA 0.434700 ;
    PORT
      LAYER met3 ;
        RECT 0.000 163.240 4.000 163.840 ;
    END
  END wb_adr_i[7]
  PIN wb_adr_i[8]
    DIRECTION INPUT ;
    USE SIGNAL ;
    ANTENNAGATEAREA 0.560700 ;
    ANTENNADIFFAREA 0.434700 ;
    PORT
      LAYER met3 ;
        RECT 376.000 149.640 380.000 150.240 ;
    END
  END wb_adr_i[8]
  PIN wb_adr_i[9]
    DIRECTION INPUT ;
    USE SIGNAL ;
    ANTENNAGATEAREA 0.560700 ;
    ANTENNADIFFAREA 0.434700 ;
    PORT
      LAYER met3 ;
        RECT 376.000 231.240 380.000 231.840 ;
    END
  END wb_adr_i[9]
  PIN wb_clk_i
    DIRECTION INPUT ;
    USE SIGNAL ;
    ANTENNAGATEAREA 1.286700 ;
    ANTENNADIFFAREA 0.434700 ;
    PORT
      LAYER met2 ;
        RECT 90.250 0.000 90.530 4.000 ;
    END
  END wb_clk_i
  PIN wb_cyc_i
    DIRECTION INPUT ;
    USE SIGNAL ;
    ANTENNAGATEAREA 0.560700 ;
    ANTENNADIFFAREA 0.434700 ;
    PORT
      LAYER met2 ;
        RECT 193.290 0.000 193.570 4.000 ;
    END
  END wb_cyc_i
  PIN wb_dat_i[0]
    DIRECTION INPUT ;
    USE SIGNAL ;
    ANTENNAGATEAREA 0.560700 ;
    ANTENNADIFFAREA 0.434700 ;
    PORT
      LAYER met2 ;
        RECT 67.710 376.000 67.990 380.000 ;
    END
  END wb_dat_i[0]
  PIN wb_dat_i[10]
    DIRECTION INPUT ;
    USE SIGNAL ;
    ANTENNAGATEAREA 0.560700 ;
    ANTENNADIFFAREA 0.434700 ;
    PORT
      LAYER met2 ;
        RECT 112.790 376.000 113.070 380.000 ;
    END
  END wb_dat_i[10]
  PIN wb_dat_i[11]
    DIRECTION INPUT ;
    USE SIGNAL ;
    ANTENNAGATEAREA 0.560700 ;
    ANTENNADIFFAREA 0.434700 ;
    PORT
      LAYER met2 ;
        RECT 119.230 376.000 119.510 380.000 ;
    END
  END wb_dat_i[11]
  PIN wb_dat_i[12]
    DIRECTION INPUT ;
    USE SIGNAL ;
    ANTENNAGATEAREA 0.560700 ;
    ANTENNADIFFAREA 0.434700 ;
    PORT
      LAYER met2 ;
        RECT 125.670 376.000 125.950 380.000 ;
    END
  END wb_dat_i[12]
  PIN wb_dat_i[13]
    DIRECTION INPUT ;
    USE SIGNAL ;
    ANTENNAGATEAREA 0.560700 ;
    ANTENNADIFFAREA 0.434700 ;
    PORT
      LAYER met3 ;
        RECT 0.000 258.440 4.000 259.040 ;
    END
  END wb_dat_i[13]
  PIN wb_dat_i[14]
    DIRECTION INPUT ;
    USE SIGNAL ;
    ANTENNAGATEAREA 0.560700 ;
    ANTENNADIFFAREA 0.434700 ;
    PORT
      LAYER met2 ;
        RECT 180.410 376.000 180.690 380.000 ;
    END
  END wb_dat_i[14]
  PIN wb_dat_i[15]
    DIRECTION INPUT ;
    USE SIGNAL ;
    ANTENNAGATEAREA 0.560700 ;
    ANTENNADIFFAREA 0.434700 ;
    PORT
      LAYER met2 ;
        RECT 318.870 376.000 319.150 380.000 ;
    END
  END wb_dat_i[15]
  PIN wb_dat_i[16]
    DIRECTION INPUT ;
    USE SIGNAL ;
    ANTENNAGATEAREA 0.560700 ;
    ANTENNADIFFAREA 0.434700 ;
    PORT
      LAYER met2 ;
        RECT 286.670 376.000 286.950 380.000 ;
    END
  END wb_dat_i[16]
  PIN wb_dat_i[17]
    DIRECTION INPUT ;
    USE SIGNAL ;
    ANTENNAGATEAREA 0.560700 ;
    ANTENNADIFFAREA 0.434700 ;
    PORT
      LAYER met2 ;
        RECT 260.910 376.000 261.190 380.000 ;
    END
  END wb_dat_i[17]
  PIN wb_dat_i[18]
    DIRECTION INPUT ;
    USE SIGNAL ;
    ANTENNAGATEAREA 0.560700 ;
    ANTENNADIFFAREA 0.434700 ;
    PORT
      LAYER met2 ;
        RECT 183.630 376.000 183.910 380.000 ;
    END
  END wb_dat_i[18]
  PIN wb_dat_i[19]
    DIRECTION INPUT ;
    USE SIGNAL ;
    ANTENNAGATEAREA 0.560700 ;
    ANTENNADIFFAREA 0.434700 ;
    PORT
      LAYER met2 ;
        RECT 264.130 376.000 264.410 380.000 ;
    END
  END wb_dat_i[19]
  PIN wb_dat_i[1]
    DIRECTION INPUT ;
    USE SIGNAL ;
    ANTENNAGATEAREA 0.560700 ;
    ANTENNADIFFAREA 0.434700 ;
    PORT
      LAYER met2 ;
        RECT 61.270 376.000 61.550 380.000 ;
    END
  END wb_dat_i[1]
  PIN wb_dat_i[20]
    DIRECTION INPUT ;
    USE SIGNAL ;
    ANTENNAGATEAREA 0.560700 ;
    ANTENNADIFFAREA 0.434700 ;
    PORT
      LAYER met2 ;
        RECT 109.570 376.000 109.850 380.000 ;
    END
  END wb_dat_i[20]
  PIN wb_dat_i[21]
    DIRECTION INPUT ;
    USE SIGNAL ;
    ANTENNAGATEAREA 0.560700 ;
    ANTENNADIFFAREA 0.434700 ;
    PORT
      LAYER met2 ;
        RECT 122.450 376.000 122.730 380.000 ;
    END
  END wb_dat_i[21]
  PIN wb_dat_i[22]
    DIRECTION INPUT ;
    USE SIGNAL ;
    ANTENNAGATEAREA 0.560700 ;
    ANTENNADIFFAREA 0.434700 ;
    PORT
      LAYER met3 ;
        RECT 0.000 241.440 4.000 242.040 ;
    END
  END wb_dat_i[22]
  PIN wb_dat_i[23]
    DIRECTION INPUT ;
    USE SIGNAL ;
    ANTENNAGATEAREA 0.560700 ;
    ANTENNADIFFAREA 0.434700 ;
    PORT
      LAYER met2 ;
        RECT 222.270 376.000 222.550 380.000 ;
    END
  END wb_dat_i[23]
  PIN wb_dat_i[24]
    DIRECTION INPUT ;
    USE SIGNAL ;
    ANTENNAGATEAREA 0.560700 ;
    ANTENNADIFFAREA 0.434700 ;
    PORT
      LAYER met2 ;
        RECT 103.130 376.000 103.410 380.000 ;
    END
  END wb_dat_i[24]
  PIN wb_dat_i[25]
    DIRECTION INPUT ;
    USE SIGNAL ;
    ANTENNAGATEAREA 0.560700 ;
    ANTENNADIFFAREA 0.434700 ;
    PORT
      LAYER met2 ;
        RECT 161.090 376.000 161.370 380.000 ;
    END
  END wb_dat_i[25]
  PIN wb_dat_i[26]
    DIRECTION INPUT ;
    USE SIGNAL ;
    ANTENNAGATEAREA 0.560700 ;
    ANTENNADIFFAREA 0.434700 ;
    PORT
      LAYER met2 ;
        RECT 244.810 376.000 245.090 380.000 ;
    END
  END wb_dat_i[26]
  PIN wb_dat_i[27]
    DIRECTION INPUT ;
    USE SIGNAL ;
    ANTENNAGATEAREA 0.560700 ;
    ANTENNADIFFAREA 0.434700 ;
    PORT
      LAYER met2 ;
        RECT 206.170 376.000 206.450 380.000 ;
    END
  END wb_dat_i[27]
  PIN wb_dat_i[28]
    DIRECTION INPUT ;
    USE SIGNAL ;
    ANTENNAGATEAREA 0.560700 ;
    ANTENNADIFFAREA 0.434700 ;
    PORT
      LAYER met2 ;
        RECT 64.490 376.000 64.770 380.000 ;
    END
  END wb_dat_i[28]
  PIN wb_dat_i[29]
    DIRECTION INPUT ;
    USE SIGNAL ;
    ANTENNAGATEAREA 0.560700 ;
    ANTENNADIFFAREA 0.434700 ;
    PORT
      LAYER met2 ;
        RECT 173.970 376.000 174.250 380.000 ;
    END
  END wb_dat_i[29]
  PIN wb_dat_i[2]
    DIRECTION INPUT ;
    USE SIGNAL ;
    ANTENNAGATEAREA 0.560700 ;
    ANTENNADIFFAREA 0.434700 ;
    PORT
      LAYER met2 ;
        RECT 267.350 376.000 267.630 380.000 ;
    END
  END wb_dat_i[2]
  PIN wb_dat_i[30]
    DIRECTION INPUT ;
    USE SIGNAL ;
    ANTENNAGATEAREA 0.560700 ;
    ANTENNADIFFAREA 0.434700 ;
    PORT
      LAYER met2 ;
        RECT 144.990 376.000 145.270 380.000 ;
    END
  END wb_dat_i[30]
  PIN wb_dat_i[31]
    DIRECTION INPUT ;
    USE SIGNAL ;
    ANTENNAGATEAREA 0.560700 ;
    ANTENNADIFFAREA 0.434700 ;
    PORT
      LAYER met2 ;
        RECT 273.790 376.000 274.070 380.000 ;
    END
  END wb_dat_i[31]
  PIN wb_dat_i[3]
    DIRECTION INPUT ;
    USE SIGNAL ;
    ANTENNAGATEAREA 0.560700 ;
    ANTENNADIFFAREA 0.434700 ;
    PORT
      LAYER met2 ;
        RECT 231.930 376.000 232.210 380.000 ;
    END
  END wb_dat_i[3]
  PIN wb_dat_i[4]
    DIRECTION INPUT ;
    USE SIGNAL ;
    ANTENNAGATEAREA 0.560700 ;
    ANTENNADIFFAREA 0.434700 ;
    PORT
      LAYER met2 ;
        RECT 277.010 376.000 277.290 380.000 ;
    END
  END wb_dat_i[4]
  PIN wb_dat_i[5]
    DIRECTION INPUT ;
    USE SIGNAL ;
    ANTENNAGATEAREA 0.560700 ;
    ANTENNADIFFAREA 0.434700 ;
    PORT
      LAYER met2 ;
        RECT 157.870 376.000 158.150 380.000 ;
    END
  END wb_dat_i[5]
  PIN wb_dat_i[6]
    DIRECTION INPUT ;
    USE SIGNAL ;
    ANTENNAGATEAREA 0.560700 ;
    ANTENNADIFFAREA 0.434700 ;
    PORT
      LAYER met2 ;
        RECT 199.730 376.000 200.010 380.000 ;
    END
  END wb_dat_i[6]
  PIN wb_dat_i[7]
    DIRECTION INPUT ;
    USE SIGNAL ;
    ANTENNAGATEAREA 0.560700 ;
    ANTENNADIFFAREA 0.434700 ;
    PORT
      LAYER met2 ;
        RECT 138.550 376.000 138.830 380.000 ;
    END
  END wb_dat_i[7]
  PIN wb_dat_i[8]
    DIRECTION INPUT ;
    USE SIGNAL ;
    ANTENNAGATEAREA 0.560700 ;
    ANTENNADIFFAREA 0.434700 ;
    PORT
      LAYER met2 ;
        RECT 225.490 376.000 225.770 380.000 ;
    END
  END wb_dat_i[8]
  PIN wb_dat_i[9]
    DIRECTION INPUT ;
    USE SIGNAL ;
    ANTENNAGATEAREA 0.560700 ;
    ANTENNADIFFAREA 0.434700 ;
    PORT
      LAYER met2 ;
        RECT 322.090 376.000 322.370 380.000 ;
    END
  END wb_dat_i[9]
  PIN wb_dat_o[0]
    DIRECTION OUTPUT ;
    USE SIGNAL ;
    ANTENNADIFFAREA 1.782000 ;
    PORT
      LAYER met2 ;
        RECT 183.630 0.000 183.910 4.000 ;
    END
  END wb_dat_o[0]
  PIN wb_dat_o[10]
    DIRECTION OUTPUT ;
    USE SIGNAL ;
    ANTENNADIFFAREA 1.782000 ;
    PORT
      LAYER met2 ;
        RECT 87.030 0.000 87.310 4.000 ;
    END
  END wb_dat_o[10]
  PIN wb_dat_o[11]
    DIRECTION OUTPUT ;
    USE SIGNAL ;
    ANTENNADIFFAREA 1.782000 ;
    PORT
      LAYER met2 ;
        RECT 277.010 0.000 277.290 4.000 ;
    END
  END wb_dat_o[11]
  PIN wb_dat_o[12]
    DIRECTION OUTPUT ;
    USE SIGNAL ;
    ANTENNADIFFAREA 1.782000 ;
    PORT
      LAYER met2 ;
        RECT 244.810 0.000 245.090 4.000 ;
    END
  END wb_dat_o[12]
  PIN wb_dat_o[13]
    DIRECTION OUTPUT ;
    USE SIGNAL ;
    ANTENNADIFFAREA 1.782000 ;
    PORT
      LAYER met2 ;
        RECT 144.990 0.000 145.270 4.000 ;
    END
  END wb_dat_o[13]
  PIN wb_dat_o[14]
    DIRECTION OUTPUT ;
    USE SIGNAL ;
    ANTENNADIFFAREA 1.782000 ;
    PORT
      LAYER met3 ;
        RECT 0.000 136.040 4.000 136.640 ;
    END
  END wb_dat_o[14]
  PIN wb_dat_o[15]
    DIRECTION OUTPUT ;
    USE SIGNAL ;
    ANTENNADIFFAREA 1.782000 ;
    PORT
      LAYER met2 ;
        RECT 112.790 0.000 113.070 4.000 ;
    END
  END wb_dat_o[15]
  PIN wb_dat_o[16]
    DIRECTION OUTPUT ;
    USE SIGNAL ;
    ANTENNADIFFAREA 1.782000 ;
    PORT
      LAYER met2 ;
        RECT 151.430 0.000 151.710 4.000 ;
    END
  END wb_dat_o[16]
  PIN wb_dat_o[17]
    DIRECTION OUTPUT ;
    USE SIGNAL ;
    ANTENNADIFFAREA 1.782000 ;
    PORT
      LAYER met2 ;
        RECT 238.370 0.000 238.650 4.000 ;
    END
  END wb_dat_o[17]
  PIN wb_dat_o[18]
    DIRECTION OUTPUT ;
    USE SIGNAL ;
    ANTENNADIFFAREA 1.782000 ;
    PORT
      LAYER met2 ;
        RECT 222.270 0.000 222.550 4.000 ;
    END
  END wb_dat_o[18]
  PIN wb_dat_o[19]
    DIRECTION OUTPUT ;
    USE SIGNAL ;
    ANTENNADIFFAREA 1.782000 ;
    PORT
      LAYER met2 ;
        RECT 273.790 0.000 274.070 4.000 ;
    END
  END wb_dat_o[19]
  PIN wb_dat_o[1]
    DIRECTION OUTPUT ;
    USE SIGNAL ;
    ANTENNADIFFAREA 1.782000 ;
    PORT
      LAYER met2 ;
        RECT 141.770 0.000 142.050 4.000 ;
    END
  END wb_dat_o[1]
  PIN wb_dat_o[20]
    DIRECTION OUTPUT ;
    USE SIGNAL ;
    ANTENNADIFFAREA 1.782000 ;
    PORT
      LAYER met2 ;
        RECT 99.910 0.000 100.190 4.000 ;
    END
  END wb_dat_o[20]
  PIN wb_dat_o[21]
    DIRECTION OUTPUT ;
    USE SIGNAL ;
    ANTENNADIFFAREA 1.782000 ;
    PORT
      LAYER met2 ;
        RECT 299.550 0.000 299.830 4.000 ;
    END
  END wb_dat_o[21]
  PIN wb_dat_o[22]
    DIRECTION OUTPUT ;
    USE SIGNAL ;
    ANTENNADIFFAREA 1.782000 ;
    PORT
      LAYER met2 ;
        RECT 280.230 0.000 280.510 4.000 ;
    END
  END wb_dat_o[22]
  PIN wb_dat_o[23]
    DIRECTION OUTPUT ;
    USE SIGNAL ;
    ANTENNADIFFAREA 1.782000 ;
    PORT
      LAYER met2 ;
        RECT 67.710 0.000 67.990 4.000 ;
    END
  END wb_dat_o[23]
  PIN wb_dat_o[24]
    DIRECTION OUTPUT ;
    USE SIGNAL ;
    ANTENNADIFFAREA 1.782000 ;
    PORT
      LAYER met2 ;
        RECT 264.130 0.000 264.410 4.000 ;
    END
  END wb_dat_o[24]
  PIN wb_dat_o[25]
    DIRECTION OUTPUT ;
    USE SIGNAL ;
    ANTENNADIFFAREA 1.782000 ;
    PORT
      LAYER met2 ;
        RECT 235.150 0.000 235.430 4.000 ;
    END
  END wb_dat_o[25]
  PIN wb_dat_o[26]
    DIRECTION OUTPUT ;
    USE SIGNAL ;
    ANTENNADIFFAREA 1.782000 ;
    PORT
      LAYER met2 ;
        RECT 61.270 0.000 61.550 4.000 ;
    END
  END wb_dat_o[26]
  PIN wb_dat_o[27]
    DIRECTION OUTPUT ;
    USE SIGNAL ;
    ANTENNADIFFAREA 1.782000 ;
    PORT
      LAYER met2 ;
        RECT 283.450 0.000 283.730 4.000 ;
    END
  END wb_dat_o[27]
  PIN wb_dat_o[28]
    DIRECTION OUTPUT ;
    USE SIGNAL ;
    ANTENNADIFFAREA 1.782000 ;
    PORT
      LAYER met2 ;
        RECT 305.990 0.000 306.270 4.000 ;
    END
  END wb_dat_o[28]
  PIN wb_dat_o[29]
    DIRECTION OUTPUT ;
    USE SIGNAL ;
    ANTENNADIFFAREA 1.782000 ;
    PORT
      LAYER met2 ;
        RECT 135.330 0.000 135.610 4.000 ;
    END
  END wb_dat_o[29]
  PIN wb_dat_o[2]
    DIRECTION OUTPUT ;
    USE SIGNAL ;
    ANTENNADIFFAREA 1.782000 ;
    PORT
      LAYER met2 ;
        RECT 116.010 0.000 116.290 4.000 ;
    END
  END wb_dat_o[2]
  PIN wb_dat_o[30]
    DIRECTION OUTPUT ;
    USE SIGNAL ;
    ANTENNADIFFAREA 1.782000 ;
    PORT
      LAYER met2 ;
        RECT 199.730 0.000 200.010 4.000 ;
    END
  END wb_dat_o[30]
  PIN wb_dat_o[31]
    DIRECTION OUTPUT ;
    USE SIGNAL ;
    ANTENNADIFFAREA 1.782000 ;
    PORT
      LAYER met2 ;
        RECT 77.370 0.000 77.650 4.000 ;
    END
  END wb_dat_o[31]
  PIN wb_dat_o[3]
    DIRECTION OUTPUT ;
    USE SIGNAL ;
    ANTENNADIFFAREA 1.782000 ;
    PORT
      LAYER met2 ;
        RECT 241.590 0.000 241.870 4.000 ;
    END
  END wb_dat_o[3]
  PIN wb_dat_o[4]
    DIRECTION OUTPUT ;
    USE SIGNAL ;
    ANTENNADIFFAREA 1.782000 ;
    PORT
      LAYER met2 ;
        RECT 157.870 0.000 158.150 4.000 ;
    END
  END wb_dat_o[4]
  PIN wb_dat_o[5]
    DIRECTION OUTPUT ;
    USE SIGNAL ;
    ANTENNADIFFAREA 1.782000 ;
    PORT
      LAYER met2 ;
        RECT 219.050 0.000 219.330 4.000 ;
    END
  END wb_dat_o[5]
  PIN wb_dat_o[6]
    DIRECTION OUTPUT ;
    USE SIGNAL ;
    ANTENNADIFFAREA 1.782000 ;
    PORT
      LAYER met2 ;
        RECT 257.690 0.000 257.970 4.000 ;
    END
  END wb_dat_o[6]
  PIN wb_dat_o[7]
    DIRECTION OUTPUT ;
    USE SIGNAL ;
    ANTENNADIFFAREA 1.782000 ;
    PORT
      LAYER met2 ;
        RECT 109.570 0.000 109.850 4.000 ;
    END
  END wb_dat_o[7]
  PIN wb_dat_o[8]
    DIRECTION OUTPUT ;
    USE SIGNAL ;
    ANTENNADIFFAREA 1.782000 ;
    PORT
      LAYER met2 ;
        RECT 70.930 0.000 71.210 4.000 ;
    END
  END wb_dat_o[8]
  PIN wb_dat_o[9]
    DIRECTION OUTPUT ;
    USE SIGNAL ;
    ANTENNADIFFAREA 1.782000 ;
    PORT
      LAYER met2 ;
        RECT 128.890 0.000 129.170 4.000 ;
    END
  END wb_dat_o[9]
  PIN wb_rst_i
    DIRECTION INPUT ;
    USE SIGNAL ;
    ANTENNAGATEAREA 0.647700 ;
    ANTENNADIFFAREA 0.434700 ;
    PORT
      LAYER met3 ;
        RECT 0.000 255.040 4.000 255.640 ;
    END
  END wb_rst_i
  PIN wb_sel_i[0]
    DIRECTION INPUT ;
    USE SIGNAL ;
    ANTENNAGATEAREA 0.560700 ;
    ANTENNADIFFAREA 0.434700 ;
    PORT
      LAYER met2 ;
        RECT 212.610 376.000 212.890 380.000 ;
    END
  END wb_sel_i[0]
  PIN wb_sel_i[1]
    DIRECTION INPUT ;
    USE SIGNAL ;
    ANTENNAGATEAREA 0.560700 ;
    ANTENNADIFFAREA 0.434700 ;
    PORT
      LAYER met2 ;
        RECT 305.990 376.000 306.270 380.000 ;
    END
  END wb_sel_i[1]
  PIN wb_sel_i[2]
    DIRECTION INPUT ;
    USE SIGNAL ;
    ANTENNAGATEAREA 0.560700 ;
    ANTENNADIFFAREA 0.434700 ;
    PORT
      LAYER met3 ;
        RECT 0.000 238.040 4.000 238.640 ;
    END
  END wb_sel_i[2]
  PIN wb_sel_i[3]
    DIRECTION INPUT ;
    USE SIGNAL ;
    ANTENNAGATEAREA 0.560700 ;
    ANTENNADIFFAREA 0.434700 ;
    PORT
      LAYER met2 ;
        RECT 270.570 376.000 270.850 380.000 ;
    END
  END wb_sel_i[3]
  PIN wb_stb_i
    DIRECTION INPUT ;
    USE SIGNAL ;
    ANTENNAGATEAREA 0.560700 ;
    ANTENNADIFFAREA 0.434700 ;
    PORT
      LAYER met2 ;
        RECT 212.610 0.000 212.890 4.000 ;
    END
  END wb_stb_i
  PIN wb_we_i
    DIRECTION INPUT ;
    USE SIGNAL ;
    ANTENNAGATEAREA 0.560700 ;
    ANTENNADIFFAREA 0.434700 ;
    PORT
      LAYER met2 ;
        RECT 206.170 0.000 206.450 4.000 ;
    END
  END wb_we_i
  OBS
      LAYER nwell ;
        RECT 5.330 10.795 374.630 367.390 ;
      LAYER li1 ;
        RECT 5.520 10.795 374.440 367.285 ;
      LAYER met1 ;
        RECT 4.210 0.380 374.830 374.640 ;
      LAYER met2 ;
        RECT 4.230 375.720 57.770 376.000 ;
        RECT 58.610 375.720 60.990 376.000 ;
        RECT 61.830 375.720 64.210 376.000 ;
        RECT 65.050 375.720 67.430 376.000 ;
        RECT 68.270 375.720 70.650 376.000 ;
        RECT 71.490 375.720 73.870 376.000 ;
        RECT 74.710 375.720 77.090 376.000 ;
        RECT 77.930 375.720 80.310 376.000 ;
        RECT 81.150 375.720 83.530 376.000 ;
        RECT 84.370 375.720 86.750 376.000 ;
        RECT 87.590 375.720 89.970 376.000 ;
        RECT 90.810 375.720 93.190 376.000 ;
        RECT 94.030 375.720 96.410 376.000 ;
        RECT 97.250 375.720 99.630 376.000 ;
        RECT 100.470 375.720 102.850 376.000 ;
        RECT 103.690 375.720 106.070 376.000 ;
        RECT 106.910 375.720 109.290 376.000 ;
        RECT 110.130 375.720 112.510 376.000 ;
        RECT 113.350 375.720 115.730 376.000 ;
        RECT 116.570 375.720 118.950 376.000 ;
        RECT 119.790 375.720 122.170 376.000 ;
        RECT 123.010 375.720 125.390 376.000 ;
        RECT 126.230 375.720 128.610 376.000 ;
        RECT 129.450 375.720 131.830 376.000 ;
        RECT 132.670 375.720 135.050 376.000 ;
        RECT 135.890 375.720 138.270 376.000 ;
        RECT 139.110 375.720 141.490 376.000 ;
        RECT 142.330 375.720 144.710 376.000 ;
        RECT 145.550 375.720 147.930 376.000 ;
        RECT 148.770 375.720 151.150 376.000 ;
        RECT 151.990 375.720 154.370 376.000 ;
        RECT 155.210 375.720 157.590 376.000 ;
        RECT 158.430 375.720 160.810 376.000 ;
        RECT 161.650 375.720 164.030 376.000 ;
        RECT 164.870 375.720 167.250 376.000 ;
        RECT 168.090 375.720 170.470 376.000 ;
        RECT 171.310 375.720 173.690 376.000 ;
        RECT 174.530 375.720 176.910 376.000 ;
        RECT 177.750 375.720 180.130 376.000 ;
        RECT 180.970 375.720 183.350 376.000 ;
        RECT 184.190 375.720 186.570 376.000 ;
        RECT 187.410 375.720 189.790 376.000 ;
        RECT 190.630 375.720 193.010 376.000 ;
        RECT 193.850 375.720 196.230 376.000 ;
        RECT 197.070 375.720 199.450 376.000 ;
        RECT 200.290 375.720 202.670 376.000 ;
        RECT 203.510 375.720 205.890 376.000 ;
        RECT 206.730 375.720 209.110 376.000 ;
        RECT 209.950 375.720 212.330 376.000 ;
        RECT 213.170 375.720 215.550 376.000 ;
        RECT 216.390 375.720 218.770 376.000 ;
        RECT 219.610 375.720 221.990 376.000 ;
        RECT 222.830 375.720 225.210 376.000 ;
        RECT 226.050 375.720 228.430 376.000 ;
        RECT 229.270 375.720 231.650 376.000 ;
        RECT 232.490 375.720 234.870 376.000 ;
        RECT 235.710 375.720 238.090 376.000 ;
        RECT 238.930 375.720 241.310 376.000 ;
        RECT 242.150 375.720 244.530 376.000 ;
        RECT 245.370 375.720 247.750 376.000 ;
        RECT 248.590 375.720 250.970 376.000 ;
        RECT 251.810 375.720 254.190 376.000 ;
        RECT 255.030 375.720 257.410 376.000 ;
        RECT 258.250 375.720 260.630 376.000 ;
        RECT 261.470 375.720 263.850 376.000 ;
        RECT 264.690 375.720 267.070 376.000 ;
        RECT 267.910 375.720 270.290 376.000 ;
        RECT 271.130 375.720 273.510 376.000 ;
        RECT 274.350 375.720 276.730 376.000 ;
        RECT 277.570 375.720 279.950 376.000 ;
        RECT 280.790 375.720 283.170 376.000 ;
        RECT 284.010 375.720 286.390 376.000 ;
        RECT 287.230 375.720 289.610 376.000 ;
        RECT 290.450 375.720 292.830 376.000 ;
        RECT 293.670 375.720 296.050 376.000 ;
        RECT 296.890 375.720 299.270 376.000 ;
        RECT 300.110 375.720 302.490 376.000 ;
        RECT 303.330 375.720 305.710 376.000 ;
        RECT 306.550 375.720 308.930 376.000 ;
        RECT 309.770 375.720 312.150 376.000 ;
        RECT 312.990 375.720 315.370 376.000 ;
        RECT 316.210 375.720 318.590 376.000 ;
        RECT 319.430 375.720 321.810 376.000 ;
        RECT 322.650 375.720 325.030 376.000 ;
        RECT 325.870 375.720 374.810 376.000 ;
        RECT 4.230 4.280 374.810 375.720 ;
        RECT 4.230 0.350 54.550 4.280 ;
        RECT 55.390 0.350 57.770 4.280 ;
        RECT 58.610 0.350 60.990 4.280 ;
        RECT 61.830 0.350 64.210 4.280 ;
        RECT 65.050 0.350 67.430 4.280 ;
        RECT 68.270 0.350 70.650 4.280 ;
        RECT 71.490 0.350 73.870 4.280 ;
        RECT 74.710 0.350 77.090 4.280 ;
        RECT 77.930 0.350 80.310 4.280 ;
        RECT 81.150 0.350 83.530 4.280 ;
        RECT 84.370 0.350 86.750 4.280 ;
        RECT 87.590 0.350 89.970 4.280 ;
        RECT 90.810 0.350 93.190 4.280 ;
        RECT 94.030 0.350 96.410 4.280 ;
        RECT 97.250 0.350 99.630 4.280 ;
        RECT 100.470 0.350 102.850 4.280 ;
        RECT 103.690 0.350 106.070 4.280 ;
        RECT 106.910 0.350 109.290 4.280 ;
        RECT 110.130 0.350 112.510 4.280 ;
        RECT 113.350 0.350 115.730 4.280 ;
        RECT 116.570 0.350 118.950 4.280 ;
        RECT 119.790 0.350 122.170 4.280 ;
        RECT 123.010 0.350 125.390 4.280 ;
        RECT 126.230 0.350 128.610 4.280 ;
        RECT 129.450 0.350 131.830 4.280 ;
        RECT 132.670 0.350 135.050 4.280 ;
        RECT 135.890 0.350 138.270 4.280 ;
        RECT 139.110 0.350 141.490 4.280 ;
        RECT 142.330 0.350 144.710 4.280 ;
        RECT 145.550 0.350 147.930 4.280 ;
        RECT 148.770 0.350 151.150 4.280 ;
        RECT 151.990 0.350 154.370 4.280 ;
        RECT 155.210 0.350 157.590 4.280 ;
        RECT 158.430 0.350 160.810 4.280 ;
        RECT 161.650 0.350 164.030 4.280 ;
        RECT 164.870 0.350 167.250 4.280 ;
        RECT 168.090 0.350 170.470 4.280 ;
        RECT 171.310 0.350 173.690 4.280 ;
        RECT 174.530 0.350 176.910 4.280 ;
        RECT 177.750 0.350 180.130 4.280 ;
        RECT 180.970 0.350 183.350 4.280 ;
        RECT 184.190 0.350 186.570 4.280 ;
        RECT 187.410 0.350 189.790 4.280 ;
        RECT 190.630 0.350 193.010 4.280 ;
        RECT 193.850 0.350 196.230 4.280 ;
        RECT 197.070 0.350 199.450 4.280 ;
        RECT 200.290 0.350 202.670 4.280 ;
        RECT 203.510 0.350 205.890 4.280 ;
        RECT 206.730 0.350 209.110 4.280 ;
        RECT 209.950 0.350 212.330 4.280 ;
        RECT 213.170 0.350 215.550 4.280 ;
        RECT 216.390 0.350 218.770 4.280 ;
        RECT 219.610 0.350 221.990 4.280 ;
        RECT 222.830 0.350 225.210 4.280 ;
        RECT 226.050 0.350 228.430 4.280 ;
        RECT 229.270 0.350 231.650 4.280 ;
        RECT 232.490 0.350 234.870 4.280 ;
        RECT 235.710 0.350 238.090 4.280 ;
        RECT 238.930 0.350 241.310 4.280 ;
        RECT 242.150 0.350 244.530 4.280 ;
        RECT 245.370 0.350 247.750 4.280 ;
        RECT 248.590 0.350 250.970 4.280 ;
        RECT 251.810 0.350 254.190 4.280 ;
        RECT 255.030 0.350 257.410 4.280 ;
        RECT 258.250 0.350 260.630 4.280 ;
        RECT 261.470 0.350 263.850 4.280 ;
        RECT 264.690 0.350 267.070 4.280 ;
        RECT 267.910 0.350 270.290 4.280 ;
        RECT 271.130 0.350 273.510 4.280 ;
        RECT 274.350 0.350 276.730 4.280 ;
        RECT 277.570 0.350 279.950 4.280 ;
        RECT 280.790 0.350 283.170 4.280 ;
        RECT 284.010 0.350 286.390 4.280 ;
        RECT 287.230 0.350 289.610 4.280 ;
        RECT 290.450 0.350 292.830 4.280 ;
        RECT 293.670 0.350 296.050 4.280 ;
        RECT 296.890 0.350 299.270 4.280 ;
        RECT 300.110 0.350 302.490 4.280 ;
        RECT 303.330 0.350 305.710 4.280 ;
        RECT 306.550 0.350 308.930 4.280 ;
        RECT 309.770 0.350 312.150 4.280 ;
        RECT 312.990 0.350 374.810 4.280 ;
      LAYER met3 ;
        RECT 3.990 266.240 376.000 367.365 ;
        RECT 4.400 264.840 376.000 266.240 ;
        RECT 3.990 262.840 376.000 264.840 ;
        RECT 4.400 261.440 376.000 262.840 ;
        RECT 3.990 259.440 376.000 261.440 ;
        RECT 4.400 258.040 376.000 259.440 ;
        RECT 3.990 256.040 376.000 258.040 ;
        RECT 4.400 254.640 376.000 256.040 ;
        RECT 3.990 252.640 376.000 254.640 ;
        RECT 4.400 251.240 376.000 252.640 ;
        RECT 3.990 249.240 376.000 251.240 ;
        RECT 4.400 247.840 375.600 249.240 ;
        RECT 3.990 245.840 376.000 247.840 ;
        RECT 4.400 244.440 375.600 245.840 ;
        RECT 3.990 242.440 376.000 244.440 ;
        RECT 4.400 241.040 375.600 242.440 ;
        RECT 3.990 239.040 376.000 241.040 ;
        RECT 4.400 237.640 375.600 239.040 ;
        RECT 3.990 235.640 376.000 237.640 ;
        RECT 4.400 234.240 375.600 235.640 ;
        RECT 3.990 232.240 376.000 234.240 ;
        RECT 4.400 230.840 375.600 232.240 ;
        RECT 3.990 228.840 376.000 230.840 ;
        RECT 4.400 227.440 375.600 228.840 ;
        RECT 3.990 225.440 376.000 227.440 ;
        RECT 4.400 224.040 375.600 225.440 ;
        RECT 3.990 222.040 376.000 224.040 ;
        RECT 4.400 220.640 375.600 222.040 ;
        RECT 3.990 218.640 376.000 220.640 ;
        RECT 4.400 217.240 375.600 218.640 ;
        RECT 3.990 215.240 376.000 217.240 ;
        RECT 4.400 213.840 375.600 215.240 ;
        RECT 3.990 211.840 376.000 213.840 ;
        RECT 4.400 210.440 375.600 211.840 ;
        RECT 3.990 208.440 376.000 210.440 ;
        RECT 4.400 207.040 375.600 208.440 ;
        RECT 3.990 205.040 376.000 207.040 ;
        RECT 4.400 203.640 375.600 205.040 ;
        RECT 3.990 201.640 376.000 203.640 ;
        RECT 4.400 200.240 375.600 201.640 ;
        RECT 3.990 198.240 376.000 200.240 ;
        RECT 4.400 196.840 375.600 198.240 ;
        RECT 3.990 194.840 376.000 196.840 ;
        RECT 4.400 193.440 375.600 194.840 ;
        RECT 3.990 191.440 376.000 193.440 ;
        RECT 4.400 190.040 375.600 191.440 ;
        RECT 3.990 188.040 376.000 190.040 ;
        RECT 4.400 186.640 375.600 188.040 ;
        RECT 3.990 184.640 376.000 186.640 ;
        RECT 4.400 183.240 375.600 184.640 ;
        RECT 3.990 181.240 376.000 183.240 ;
        RECT 4.400 179.840 375.600 181.240 ;
        RECT 3.990 177.840 376.000 179.840 ;
        RECT 4.400 176.440 375.600 177.840 ;
        RECT 3.990 174.440 376.000 176.440 ;
        RECT 4.400 173.040 375.600 174.440 ;
        RECT 3.990 171.040 376.000 173.040 ;
        RECT 4.400 169.640 375.600 171.040 ;
        RECT 3.990 167.640 376.000 169.640 ;
        RECT 4.400 166.240 375.600 167.640 ;
        RECT 3.990 164.240 376.000 166.240 ;
        RECT 4.400 162.840 375.600 164.240 ;
        RECT 3.990 160.840 376.000 162.840 ;
        RECT 4.400 159.440 375.600 160.840 ;
        RECT 3.990 157.440 376.000 159.440 ;
        RECT 4.400 156.040 375.600 157.440 ;
        RECT 3.990 154.040 376.000 156.040 ;
        RECT 4.400 152.640 375.600 154.040 ;
        RECT 3.990 150.640 376.000 152.640 ;
        RECT 4.400 149.240 375.600 150.640 ;
        RECT 3.990 147.240 376.000 149.240 ;
        RECT 4.400 145.840 375.600 147.240 ;
        RECT 3.990 143.840 376.000 145.840 ;
        RECT 4.400 142.440 375.600 143.840 ;
        RECT 3.990 140.440 376.000 142.440 ;
        RECT 4.400 139.040 375.600 140.440 ;
        RECT 3.990 137.040 376.000 139.040 ;
        RECT 4.400 135.640 375.600 137.040 ;
        RECT 3.990 133.640 376.000 135.640 ;
        RECT 4.400 132.240 375.600 133.640 ;
        RECT 3.990 130.240 376.000 132.240 ;
        RECT 4.400 128.840 375.600 130.240 ;
        RECT 3.990 126.840 376.000 128.840 ;
        RECT 4.400 125.440 376.000 126.840 ;
        RECT 3.990 10.715 376.000 125.440 ;
      LAYER met4 ;
        RECT 206.375 11.735 206.705 28.385 ;
  END
END wb_slave_memory_mapped
END LIBRARY

